VERSION 5.8 ;
BUSBITCHARS "[]" ;
DIVIDERCHAR "/" ;
UNITS
    DATABASE MICRONS 1000 ;
END UNITS

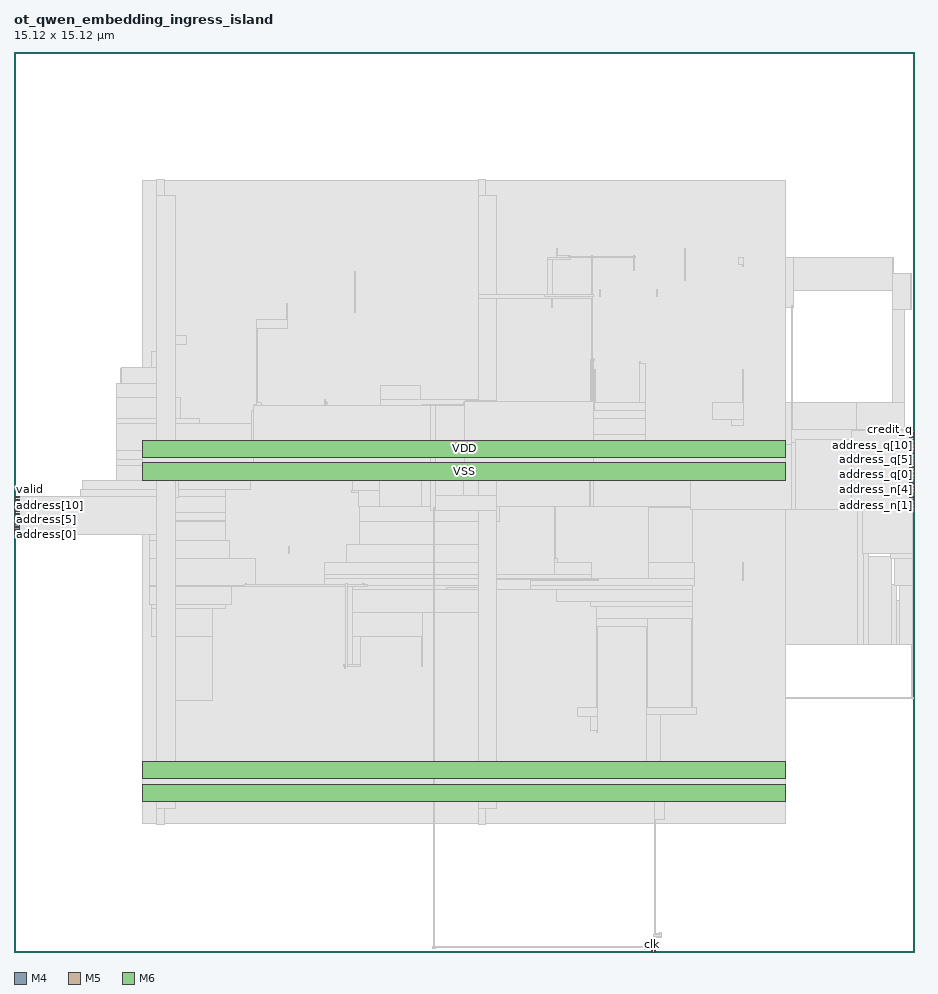
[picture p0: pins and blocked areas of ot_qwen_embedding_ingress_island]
MACRO ot_qwen_embedding_ingress_island
  FOREIGN ot_qwen_embedding_ingress_island 0 0 ;
  CLASS BLOCK ;
  SIZE 15.12 BY 15.12 ;
  PIN address[0]
    DIRECTION INPUT ;
    USE SIGNAL ;
    PORT
      LAYER M4 ;
        RECT  0 7.008 0.084 7.032 ;
    END
  END address[0]
  PIN address[10]
    DIRECTION INPUT ;
    USE SIGNAL ;
    PORT
      LAYER M4 ;
        RECT  0 7.488 0.084 7.512 ;
    END
  END address[10]
  PIN address[11]
    DIRECTION INPUT ;
    USE SIGNAL ;
    PORT
      LAYER M4 ;
        RECT  0 7.536 0.084 7.56 ;
    END
  END address[11]
  PIN address[1]
    DIRECTION INPUT ;
    USE SIGNAL ;
    PORT
      LAYER M4 ;
        RECT  0 7.056 0.084 7.08 ;
    END
  END address[1]
  PIN address[2]
    DIRECTION INPUT ;
    USE SIGNAL ;
    PORT
      LAYER M4 ;
        RECT  0 7.104 0.084 7.128 ;
    END
  END address[2]
  PIN address[3]
    DIRECTION INPUT ;
    USE SIGNAL ;
    PORT
      LAYER M4 ;
        RECT  0 7.152 0.084 7.176 ;
    END
  END address[3]
  PIN address[4]
    DIRECTION INPUT ;
    USE SIGNAL ;
    PORT
      LAYER M4 ;
        RECT  0 7.2 0.084 7.224 ;
    END
  END address[4]
  PIN address[5]
    DIRECTION INPUT ;
    USE SIGNAL ;
    PORT
      LAYER M4 ;
        RECT  0 7.248 0.084 7.272 ;
    END
  END address[5]
  PIN address[6]
    DIRECTION INPUT ;
    USE SIGNAL ;
    PORT
      LAYER M4 ;
        RECT  0 7.296 0.084 7.32 ;
    END
  END address[6]
  PIN address[7]
    DIRECTION INPUT ;
    USE SIGNAL ;
    PORT
      LAYER M4 ;
        RECT  0 7.344 0.084 7.368 ;
    END
  END address[7]
  PIN address[8]
    DIRECTION INPUT ;
    USE SIGNAL ;
    PORT
      LAYER M4 ;
        RECT  0 7.392 0.084 7.416 ;
    END
  END address[8]
  PIN address[9]
    DIRECTION INPUT ;
    USE SIGNAL ;
    PORT
      LAYER M4 ;
        RECT  0 7.44 0.084 7.464 ;
    END
  END address[9]
  PIN address_n[0]
    DIRECTION OUTPUT ;
    USE SIGNAL ;
    PORT
      LAYER M4 ;
        RECT  15.036 7.44 15.12 7.464 ;
    END
  END address_n[0]
  PIN address_n[10]
    DIRECTION OUTPUT ;
    USE SIGNAL ;
    PORT
      LAYER M4 ;
        RECT  15.036 7.92 15.12 7.944 ;
    END
  END address_n[10]
  PIN address_n[11]
    DIRECTION OUTPUT ;
    USE SIGNAL ;
    PORT
      LAYER M4 ;
        RECT  15.036 7.968 15.12 7.992 ;
    END
  END address_n[11]
  PIN address_n[1]
    DIRECTION OUTPUT ;
    USE SIGNAL ;
    PORT
      LAYER M4 ;
        RECT  15.036 7.488 15.12 7.512 ;
    END
  END address_n[1]
  PIN address_n[2]
    DIRECTION OUTPUT ;
    USE SIGNAL ;
    PORT
      LAYER M4 ;
        RECT  15.036 7.536 15.12 7.56 ;
    END
  END address_n[2]
  PIN address_n[3]
    DIRECTION OUTPUT ;
    USE SIGNAL ;
    PORT
      LAYER M4 ;
        RECT  15.036 7.584 15.12 7.608 ;
    END
  END address_n[3]
  PIN address_n[4]
    DIRECTION OUTPUT ;
    USE SIGNAL ;
    PORT
      LAYER M4 ;
        RECT  15.036 7.632 15.12 7.656 ;
    END
  END address_n[4]
  PIN address_n[5]
    DIRECTION OUTPUT ;
    USE SIGNAL ;
    PORT
      LAYER M4 ;
        RECT  15.036 7.68 15.12 7.704 ;
    END
  END address_n[5]
  PIN address_n[6]
    DIRECTION OUTPUT ;
    USE SIGNAL ;
    PORT
      LAYER M4 ;
        RECT  15.036 7.728 15.12 7.752 ;
    END
  END address_n[6]
  PIN address_n[7]
    DIRECTION OUTPUT ;
    USE SIGNAL ;
    PORT
      LAYER M4 ;
        RECT  15.036 7.776 15.12 7.8 ;
    END
  END address_n[7]
  PIN address_n[8]
    DIRECTION OUTPUT ;
    USE SIGNAL ;
    PORT
      LAYER M4 ;
        RECT  15.036 7.824 15.12 7.848 ;
    END
  END address_n[8]
  PIN address_n[9]
    DIRECTION OUTPUT ;
    USE SIGNAL ;
    PORT
      LAYER M4 ;
        RECT  15.036 7.872 15.12 7.896 ;
    END
  END address_n[9]
  PIN address_q[0]
    DIRECTION OUTPUT ;
    USE SIGNAL ;
    PORT
      LAYER M4 ;
        RECT  15.036 8.016 15.12 8.04 ;
    END
  END address_q[0]
  PIN address_q[10]
    DIRECTION OUTPUT ;
    USE SIGNAL ;
    PORT
      LAYER M4 ;
        RECT  15.036 8.496 15.12 8.52 ;
    END
  END address_q[10]
  PIN address_q[11]
    DIRECTION OUTPUT ;
    USE SIGNAL ;
    PORT
      LAYER M4 ;
        RECT  15.036 8.544 15.12 8.568 ;
    END
  END address_q[11]
  PIN address_q[1]
    DIRECTION OUTPUT ;
    USE SIGNAL ;
    PORT
      LAYER M4 ;
        RECT  15.036 8.064 15.12 8.088 ;
    END
  END address_q[1]
  PIN address_q[2]
    DIRECTION OUTPUT ;
    USE SIGNAL ;
    PORT
      LAYER M4 ;
        RECT  15.036 8.112 15.12 8.136 ;
    END
  END address_q[2]
  PIN address_q[3]
    DIRECTION OUTPUT ;
    USE SIGNAL ;
    PORT
      LAYER M4 ;
        RECT  15.036 8.16 15.12 8.184 ;
    END
  END address_q[3]
  PIN address_q[4]
    DIRECTION OUTPUT ;
    USE SIGNAL ;
    PORT
      LAYER M4 ;
        RECT  15.036 8.208 15.12 8.232 ;
    END
  END address_q[4]
  PIN address_q[5]
    DIRECTION OUTPUT ;
    USE SIGNAL ;
    PORT
      LAYER M4 ;
        RECT  15.036 8.256 15.12 8.28 ;
    END
  END address_q[5]
  PIN address_q[6]
    DIRECTION OUTPUT ;
    USE SIGNAL ;
    PORT
      LAYER M4 ;
        RECT  15.036 8.304 15.12 8.328 ;
    END
  END address_q[6]
  PIN address_q[7]
    DIRECTION OUTPUT ;
    USE SIGNAL ;
    PORT
      LAYER M4 ;
        RECT  15.036 8.352 15.12 8.376 ;
    END
  END address_q[7]
  PIN address_q[8]
    DIRECTION OUTPUT ;
    USE SIGNAL ;
    PORT
      LAYER M4 ;
        RECT  15.036 8.4 15.12 8.424 ;
    END
  END address_q[8]
  PIN address_q[9]
    DIRECTION OUTPUT ;
    USE SIGNAL ;
    PORT
      LAYER M4 ;
        RECT  15.036 8.448 15.12 8.472 ;
    END
  END address_q[9]
  PIN clk
    DIRECTION INPUT ;
    USE SIGNAL ;
    PORT
      LAYER M5 ;
        RECT  10.704 0 10.728 0.084 ;
    END
  END clk
  PIN credit
    DIRECTION INPUT ;
    USE SIGNAL ;
    PORT
      LAYER M4 ;
        RECT  0 7.584 0.084 7.608 ;
    END
  END credit
  PIN credit_n
    DIRECTION OUTPUT ;
    USE SIGNAL ;
    PORT
      LAYER M4 ;
        RECT  15.036 8.592 15.12 8.616 ;
    END
  END credit_n
  PIN credit_q
    DIRECTION OUTPUT ;
    USE SIGNAL ;
    PORT
      LAYER M4 ;
        RECT  15.036 8.64 15.12 8.664 ;
    END
  END credit_q
  PIN rst_n
    DIRECTION INPUT ;
    USE SIGNAL ;
    PORT
      LAYER M5 ;
        RECT  10.752 0 10.776 0.084 ;
    END
  END rst_n
  PIN valid
    DIRECTION INPUT ;
    USE SIGNAL ;
    PORT
      LAYER M4 ;
        RECT  0 7.632 0.084 7.656 ;
    END
  END valid
  PIN valid_n
    DIRECTION OUTPUT ;
    USE SIGNAL ;
    PORT
      LAYER M4 ;
        RECT  15.036 8.688 15.12 8.712 ;
    END
  END valid_n
  PIN valid_q
    DIRECTION OUTPUT ;
    USE SIGNAL ;
    PORT
      LAYER M4 ;
        RECT  15.036 8.736 15.12 8.76 ;
    END
  END valid_q
  PIN VDD
    DIRECTION INOUT ;
    USE POWER ;
    PORT
      LAYER M6 ;
        RECT  2.16 8.313 12.96 8.601 ;
        RECT  2.16 2.913 12.96 3.201 ;
    END
  END VDD
  PIN VSS
    DIRECTION INOUT ;
    USE GROUND ;
    PORT
      LAYER M6 ;
        RECT  2.16 7.929 12.96 8.217 ;
        RECT  2.16 2.529 12.96 2.817 ;
    END
  END VSS
  OBS
    LAYER RVTN ;
     RECT  2.16 2.16 12.96 2.295 ;
     RECT  2.16 2.565 12.96 2.835 ;
     RECT  2.16 3.105 12.96 3.375 ;
     RECT  2.16 3.645 12.96 3.915 ;
     RECT  2.16 4.185 12.96 4.455 ;
     RECT  2.16 4.725 12.96 4.995 ;
     RECT  2.16 5.265 12.96 5.535 ;
     RECT  2.16 5.805 12.96 6.075 ;
     RECT  2.16 6.345 12.96 6.615 ;
     RECT  2.16 6.885 12.96 7.155 ;
     RECT  2.16 7.425 12.96 7.695 ;
     RECT  2.16 7.965 12.96 8.235 ;
     RECT  2.16 8.505 12.96 8.775 ;
     RECT  2.16 9.045 12.96 9.315 ;
     RECT  2.16 9.585 12.96 9.855 ;
     RECT  2.16 10.125 12.96 10.395 ;
     RECT  2.16 10.665 12.96 10.935 ;
     RECT  2.16 11.205 12.96 11.475 ;
     RECT  2.16 11.745 12.96 12.015 ;
     RECT  2.16 12.285 12.96 12.555 ;
     RECT  2.16 12.825 12.96 12.96 ;
    LAYER RVTP ;
     RECT  2.16 2.295 12.96 2.565 ;
     RECT  2.16 2.835 12.96 3.105 ;
     RECT  2.16 3.375 12.96 3.645 ;
     RECT  2.16 3.915 12.96 4.185 ;
     RECT  2.16 4.455 12.96 4.725 ;
     RECT  2.16 4.995 12.96 5.265 ;
     RECT  2.16 5.535 12.96 5.805 ;
     RECT  2.16 6.075 12.96 6.345 ;
     RECT  2.16 6.615 12.96 6.885 ;
     RECT  2.16 7.155 12.96 7.425 ;
     RECT  2.16 7.695 12.96 7.965 ;
     RECT  2.16 8.235 12.96 8.505 ;
     RECT  2.16 8.775 12.96 9.045 ;
     RECT  2.16 9.315 12.96 9.585 ;
     RECT  2.16 9.855 12.96 10.125 ;
     RECT  2.16 10.395 12.96 10.665 ;
     RECT  2.16 10.935 12.96 11.205 ;
     RECT  2.16 11.475 12.96 11.745 ;
     RECT  2.16 12.015 12.96 12.285 ;
     RECT  2.16 12.555 12.96 12.825 ;
    LAYER M1 ;
     RECT  2.16 2.151 12.96 12.969 ;
    LAYER M2 ;
     RECT  0.571 7.632 1.111 7.65 ;
     RECT  1.111 7.632 1.147 7.758 ;
     RECT  1.723 9.522 1.795 9.54 ;
     RECT  1.147 7.092 2.16 7.92 ;
     RECT  1.795 9.522 2.16 9.81 ;
     RECT  2.16 2.151 12.96 12.969 ;
     RECT  12.96 10.836 13.091 11.664 ;
     RECT  12.96 5.166 14.171 9.234 ;
     RECT  14.171 5.166 14.279 8.964 ;
     RECT  14.279 5.166 14.351 7.11 ;
     RECT  14.351 5.166 14.747 6.642 ;
     RECT  13.091 11.106 14.783 11.664 ;
     RECT  14.747 5.166 14.819 6.174 ;
     RECT  14.279 8.01 14.819 8.964 ;
     RECT  14.783 11.106 14.827 11.394 ;
     RECT  14.819 5.166 14.891 5.904 ;
     RECT  14.819 8.946 14.927 8.964 ;
     RECT  14.827 10.746 14.927 11.394 ;
     RECT  14.891 5.886 14.963 5.904 ;
     RECT  14.927 10.791 15.071 11.394 ;
     RECT  12.96 4.266 15.107 4.284 ;
     RECT  14.819 8.01 15.107 8.028 ;
    LAYER M3 ;
     RECT  10.764 0.283 10.782 2.227 ;
     RECT  2.415 2.143 2.505 2.413 ;
     RECT  7.815 2.143 7.905 2.413 ;
     RECT  10.764 2.227 10.926 3.065 ;
     RECT  10.764 3.065 10.854 3.181 ;
     RECT  9.792 3.685 9.81 3.721 ;
     RECT  9.684 3.721 9.81 3.955 ;
     RECT  10.62 3.181 10.854 3.991 ;
     RECT  9.468 3.955 9.81 4.109 ;
     RECT  10.62 3.991 11.466 4.109 ;
     RECT  2.415 2.413 2.697 4.225 ;
     RECT  5.544 4.765 5.562 4.801 ;
     RECT  5.544 4.801 5.814 4.829 ;
     RECT  15.084 4.261 15.102 5.161 ;
     RECT  2.415 4.225 3.33 5.305 ;
     RECT  5.688 4.829 5.814 5.305 ;
     RECT  6.84 4.801 6.858 5.305 ;
     RECT  9.792 4.109 9.81 5.467 ;
     RECT  10.62 4.109 10.638 5.467 ;
     RECT  9.792 5.467 10.638 5.611 ;
     RECT  11.376 4.109 11.394 5.611 ;
     RECT  5.688 5.305 6.858 5.701 ;
     RECT  7.815 2.413 8.097 5.701 ;
     RECT  2.304 5.305 3.33 5.773 ;
     RECT  9.792 5.611 11.394 5.809 ;
     RECT  2.304 5.773 3.546 5.845 ;
     RECT  9.684 5.809 11.394 5.881 ;
     RECT  5.688 5.701 8.097 6.091 ;
     RECT  9.108 5.881 11.394 6.091 ;
     RECT  2.268 5.845 3.654 6.139 ;
     RECT  2.268 6.139 3.906 6.151 ;
     RECT  5.688 6.091 11.394 6.151 ;
     RECT  14.868 5.161 15.102 6.151 ;
     RECT  5.22 6.151 11.43 6.269 ;
     RECT  5.22 6.269 9.702 6.341 ;
     RECT  5.22 6.341 8.097 6.539 ;
     RECT  9.072 6.341 9.702 6.539 ;
     RECT  10.656 6.269 11.43 6.539 ;
     RECT  12.24 6.241 12.258 6.539 ;
     RECT  2.268 6.151 4.05 6.611 ;
     RECT  9.072 6.539 9.126 6.611 ;
     RECT  14.796 6.151 15.102 6.619 ;
     RECT  14.724 6.619 15.102 6.691 ;
     RECT  4.608 6.691 4.626 6.809 ;
     RECT  5.58 6.539 8.097 6.845 ;
     RECT  2.268 6.611 3.618 6.917 ;
     RECT  1.152 7.051 1.17 7.231 ;
     RECT  2.268 6.917 3.546 7.231 ;
     RECT  5.796 6.845 8.097 7.231 ;
     RECT  1.152 7.231 3.546 7.243 ;
     RECT  1.116 7.243 3.546 7.387 ;
     RECT  10.656 6.539 11.394 7.469 ;
     RECT  14.256 6.691 15.102 7.483 ;
     RECT  5.796 7.231 8.154 7.619 ;
     RECT  0.576 7.387 3.546 7.655 ;
     RECT  10.656 7.469 11.358 7.709 ;
     RECT  5.796 7.619 8.097 7.723 ;
     RECT  1.116 7.655 3.546 7.763 ;
     RECT  1.152 7.763 3.546 7.771 ;
     RECT  9.072 6.611 9.09 7.771 ;
     RECT  14.148 7.483 15.102 7.771 ;
     RECT  9.072 7.771 9.594 7.861 ;
     RECT  10.656 7.709 10.998 7.897 ;
     RECT  1.152 7.771 3.978 7.925 ;
     RECT  9 7.861 9.594 7.969 ;
     RECT  13.68 7.771 15.102 8.033 ;
     RECT  5.688 7.723 8.097 8.041 ;
     RECT  1.728 7.925 3.978 8.167 ;
     RECT  9 7.969 9.666 8.203 ;
     RECT  10.44 7.897 10.998 8.203 ;
     RECT  1.728 8.167 4.194 8.275 ;
     RECT  5.112 8.041 8.097 8.275 ;
     RECT  13.68 8.033 14.958 8.311 ;
     RECT  1.728 8.275 8.097 8.429 ;
     RECT  9 8.203 10.998 8.429 ;
     RECT  13.14 8.311 14.958 8.539 ;
     RECT  9 8.429 10.602 8.699 ;
     RECT  13.068 8.539 14.958 8.771 ;
     RECT  1.728 8.429 4.158 8.879 ;
     RECT  12.06 8.851 12.258 8.941 ;
     RECT  1.728 8.879 3.114 8.969 ;
     RECT  5.004 8.429 8.097 8.969 ;
     RECT  9.144 8.699 10.602 8.969 ;
     RECT  5.112 8.969 5.31 9.005 ;
     RECT  3.996 8.879 4.158 9.101 ;
     RECT  9.684 8.969 10.602 9.101 ;
     RECT  5.22 9.005 5.31 9.113 ;
     RECT  4.068 9.101 4.158 9.239 ;
     RECT  9.756 9.101 10.602 9.239 ;
     RECT  11.736 8.941 12.258 9.239 ;
     RECT  14.148 8.771 14.958 9.239 ;
     RECT  5.22 9.113 5.238 9.275 ;
     RECT  6.156 8.969 8.097 9.275 ;
     RECT  1.728 8.969 2.79 9.311 ;
     RECT  6.156 9.275 6.822 9.509 ;
     RECT  1.728 9.311 2.697 9.545 ;
     RECT  9.756 9.239 9.774 9.779 ;
     RECT  12.24 9.239 12.258 9.779 ;
     RECT  1.8 9.545 2.697 9.815 ;
     RECT  10.512 9.239 10.602 9.887 ;
     RECT  10.512 9.887 10.53 9.923 ;
     RECT  9.72 9.931 9.738 9.965 ;
     RECT  2.304 9.815 2.697 10.085 ;
     RECT  2.415 10.085 2.697 10.201 ;
     RECT  2.415 10.201 2.898 10.355 ;
     RECT  4.068 9.239 4.086 10.471 ;
     RECT  4.068 10.471 4.59 10.625 ;
     RECT  14.76 9.239 14.958 10.786 ;
     RECT  13.068 8.771 13.086 10.859 ;
     RECT  4.572 10.625 4.59 10.895 ;
     RECT  9.036 10.831 9.054 10.975 ;
     RECT  8.892 10.975 9.054 11.021 ;
     RECT  9.828 11.011 9.846 11.129 ;
     RECT  10.8 11.011 10.818 11.129 ;
     RECT  14.76 10.786 15.066 11.399 ;
     RECT  5.724 10.741 5.742 11.435 ;
     RECT  12.24 11.515 12.258 11.551 ;
     RECT  8.964 11.021 9.054 11.641 ;
     RECT  8.964 11.641 9.342 11.669 ;
     RECT  12.168 11.551 12.258 11.669 ;
     RECT  14.76 11.399 14.778 11.669 ;
     RECT  9.108 11.669 9.342 11.705 ;
     RECT  10.404 11.443 10.422 11.705 ;
     RECT  9.108 11.705 9.126 11.813 ;
     RECT  11.268 11.281 11.286 11.813 ;
     RECT  2.415 10.355 2.697 12.707 ;
     RECT  7.815 9.275 8.097 12.707 ;
     RECT  2.415 12.707 2.505 12.977 ;
     RECT  7.815 12.707 7.905 12.977 ;
    LAYER M4 ;
     RECT  0.06 7.008 2.408 7.656 ;
     RECT  2.408 2.148 2.512 12.972 ;
     RECT  2.512 2.418 2.704 12.702 ;
     RECT  2.704 7.632 2.765 8.424 ;
     RECT  3.877 6.144 3.923 6.168 ;
     RECT  2.765 8.4 3.985 8.424 ;
     RECT  3.985 8.4 4.067 9.096 ;
     RECT  4.067 8.4 4.493 8.424 ;
     RECT  5.209 9.216 5.267 9.24 ;
     RECT  5.533 4.8 5.603 4.824 ;
     RECT  5.677 7.728 5.785 7.752 ;
     RECT  5.845 6.144 5.933 6.168 ;
     RECT  5.785 7.488 6.145 7.752 ;
     RECT  6.145 7.488 6.853 8.52 ;
     RECT  6.853 7.488 7.549 9.096 ;
     RECT  7.261 6.096 7.808 6.12 ;
     RECT  7.549 7.488 7.808 9.24 ;
     RECT  7.808 2.148 7.912 12.972 ;
     RECT  7.912 2.418 8.104 12.702 ;
     RECT  8.104 6.096 8.669 6.264 ;
     RECT  8.104 10.992 8.963 11.016 ;
     RECT  8.104 7.488 9.673 8.52 ;
     RECT  9.673 7.488 9.685 9.096 ;
     RECT  9.685 7.488 9.731 9.96 ;
     RECT  9.731 9.936 9.749 9.96 ;
     RECT  8.669 6.24 9.821 6.264 ;
     RECT  9.313 11.664 10.433 11.688 ;
     RECT  10.597 0.048 10.739 0.072 ;
     RECT  10.753 0.288 10.883 0.312 ;
     RECT  9.731 7.488 11.365 8.52 ;
     RECT  11.365 7.44 13.057 8.52 ;
     RECT  13.057 7.44 13.129 8.568 ;
     RECT  13.129 7.44 14.065 8.616 ;
     RECT  14.065 7.44 15.084 8.76 ;
    LAYER M5 ;
     RECT  10.704 0.016 10.776 0.037 ;
     RECT  10.608 0.037 10.776 0.107 ;
     RECT  10.752 0.107 10.776 0.245 ;
     RECT  10.752 0.245 10.872 0.299 ;
     RECT  10.848 0.299 10.872 0.323 ;
     RECT  2.4 2.137 2.52 2.407 ;
     RECT  7.8 2.137 7.92 2.407 ;
     RECT  5.568 4.789 5.592 4.843 ;
     RECT  3.888 6.133 3.912 6.187 ;
     RECT  5.856 6.133 5.88 6.187 ;
     RECT  7.8 2.407 8.112 7.413 ;
     RECT  7.008 7.413 8.112 7.667 ;
     RECT  7.8 7.667 8.112 9.061 ;
     RECT  4.032 9.061 4.056 9.195 ;
     RECT  6.864 9.061 8.112 9.195 ;
     RECT  5.232 9.141 5.256 9.251 ;
     RECT  7.584 9.195 8.112 9.259 ;
     RECT  7.8 9.259 8.112 10.981 ;
     RECT  9.696 9.061 9.72 10.981 ;
     RECT  7.8 10.981 9.72 11.051 ;
     RECT  9.696 11.051 9.72 11.699 ;
     RECT  2.4 2.407 2.712 12.713 ;
     RECT  7.8 11.051 8.112 12.713 ;
     RECT  2.4 12.713 2.52 12.983 ;
     RECT  7.8 12.713 7.92 12.983 ;
    LAYER M6 ;
     RECT  2.16 7.929 4.021 8.601 ;
     RECT  5.557 4.8 5.611 4.832 ;
     RECT  3.877 6.144 5.891 6.176 ;
     RECT  4.021 7.929 6.997 9.184 ;
     RECT  7.029 0.064 7.083 0.096 ;
     RECT  6.997 7.424 7.083 9.184 ;
     RECT  7.083 7.929 7.573 9.184 ;
     RECT  7.573 7.929 9.731 9.248 ;
     RECT  8.917 11.008 9.731 11.04 ;
     RECT  7.083 0.068 10.597 0.092 ;
     RECT  10.597 0.064 10.643 0.096 ;
     RECT  10.741 0.256 10.883 0.288 ;
     RECT  2.16 2.529 12.96 3.201 ;
     RECT  9.731 7.929 12.96 8.601 ;
    LAYER M7 ;
     RECT  7.04 0.053 7.072 0.107 ;
     RECT  5.568 4.789 5.6 6.187 ;
     RECT  7.044 0.107 7.068 7.413 ;
     RECT  7.04 7.413 7.072 7.467 ;
  END
END ot_qwen_embedding_ingress_island
END LIBRARY
